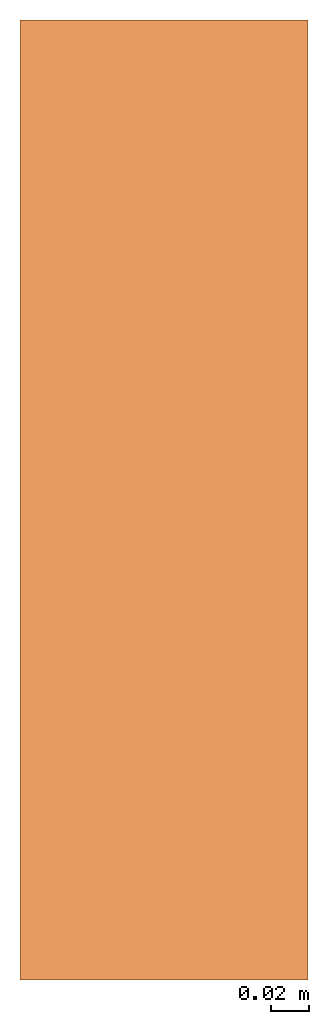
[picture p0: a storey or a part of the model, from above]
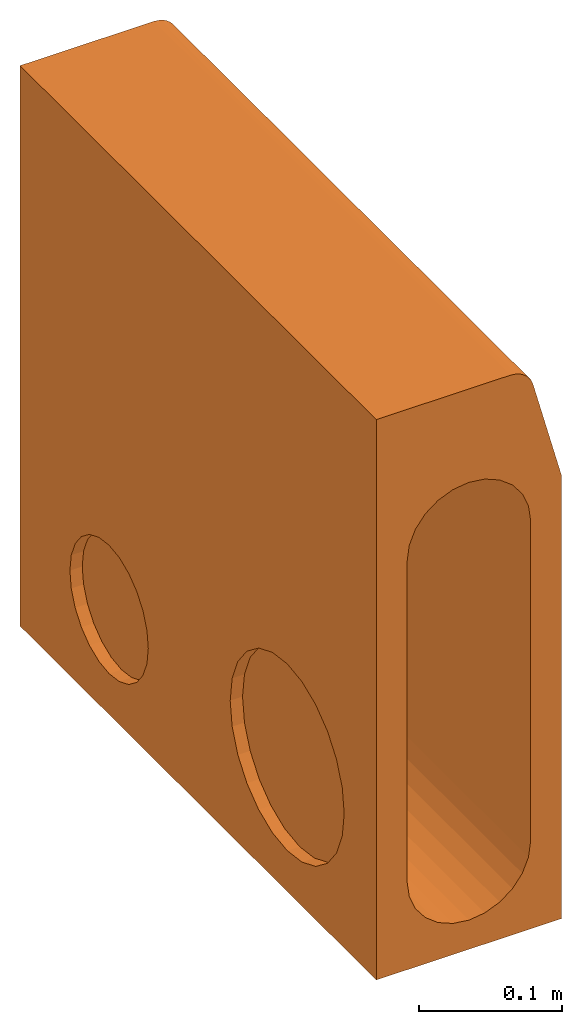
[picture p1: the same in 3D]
Properties of the parts of a building model (IFC2X3)

# File
Description: ViewDefinition [CoordinationView]
File name: 4923 - Blind Channel - 500mm LG.ifc
Time: 2013-09-18T17:36:49
Written by: Autodesk Revit 2013
Made in: 20120221_2030(x64)

# IfcProject, Project Number
LongName: Project Name; Phase: Project Status

# IfcSite, Default
RefLatitude: 42, 21, 30, 344238; RefLongitude: -71, -3, -35, -194702; RefElevation: 0 mm

# IfcBuilding
Pset_BuildingCommon - NumberOfStoreys: 2
Other - Project Issue Date: Issue Date; Project Address: Enter address here; Project Status: Project Status; Project Name: Project Name; Client Name: Owner; Project Number: Project Number

# IfcBuildingStorey (2)
Constraints - Elevation Base: 0
Graphics - Line Pattern: Center; Color: 0; Symbol: M_Level Head - Circle: M_Level Head - Circle; Symbol at End 1 Default: no; Line Weight: 1; Symbol at End 2 Default: yes
Identity Data - Structural: no; Building Story: yes
Dimensions - Computation Height: 0 mm
Name | LongName = Name | Elevation (mm) = Constraints, Elevation (mm)
T.O. Fnd. Wall | T.O. Fnd. Wall | -300
Level 1 | Level 1 | 0

# IfcBuildingElementProxy: 4923 - Blind Channel - 500mm LG, Civil-Drainage-Channel-ACO-KerbDrain-HB480(amar):4923 - Blind Channel - 500mm LG:4923 - Blind Channel - 500mm LG:481515
In: T.O. Fnd. Wall
Material: ACO Polymer Concrete.
Other - CreatedBy: www.aco.co.uk; Revision: 1
Materials and Finishes - Access Cover/Frame Colour: N/A; End Cap Colour: N/A; End Cap Material: N/A; Access Cover/Frame Finish: N/A; Channel Colour: Grey; Connection Pipe Material Colour: N/A; Access Cover/Frame Material: N/A; Connection Pipe Material: N/A; Channel Material: Vienite® Synthetic Resin Concrete
Dimensions - Mitre Void Start: 4355 mm; Mitre Void End: 4360 mm; Mitre Long end: 500 mm; Mitre Small End: 487 mm; Void Start I/O: 0 mm; Junction Start: 0 mm; Straight Void Start: 0 mm; junction void depth: 2000 mm; Void Depth: -355 mm; Void End I/O: 150 mm; I/O endcap void depth: 2000 mm; Void Width: 150 mm; Junction End: 150 mm; Void Length: 500 mm; Volume: 17011169 mm3
Constraints - Moves With Nearby Elements: no; Level: Level: Level 1
Phasing - Phase Created: Phase 1
Pset_BuildingElementProxyCommon - Reference: 4923 - Blind Channel - 500mm LG
General - SerialNumber: 0.000000; TagNumber: 0.000000
Construction - 25-11m external mitre: no; Access Unit: no; RH BS transition kerb: no; HB480-500: no; 7-6m external mitre: no; Centre Stone: no; Junction channel: no; RH inlet/outlet end cap: no; Closing end cap: no; Junction end cap: no; LH inlet/outlet end cap: no; Junction access unit: no; RH drop kerb: no; KDHB480 500_blindunit: yes; LH BS transition kerb: no; perforated centre stone: no; 10-8m external mitre: no; Bus stop kerb: no; cable loop: no; 25-11m internal mitre: no; LH drop kerb: no
Identity Data - Product Code: 4923; OmniClass Number: 23.70.50.24; Manufacturer: ACO Technologies plc - ACO Water Management Division; e-mail Sales: customersupport@aco.co.uk; URL: www.aco.co.uk; Fax: +44 (0)1462 815895; Installation guidelines: http://www.aco.co.uk/download.php?id=120; Type Comments: ACO KerbDrain HB480 half battered blind kerb unit 500mm long; Telephone: +44 (0)1462 816666; Product brochure: http://www.aco.co.uk/download.php?id=120; Address: ACO Business Park, Hitchin Road, Shefford, Bedfordshire, United Kingdom SG17 5TE; Product Page URL: http://www.aco.co.uk/product_detail.php?id=3; Maintenance guidelines: http://www.aco.co.uk/download.php?id=120 http://www.aco.co.uk/download.php?id=120; Model: ACO KerbDrain HB480; Price: POA - contact ACO; Assembly Code: D2040; OmniClass Title: Rainwater Removal; Model Description: Combined kerb and drainage system; Cost: 0; Assembly Description: Rain Water Drainage; e-mail Technical: technical@aco.co.uk
Data - Product Standard: BS EN 1433:2002, CE marked, Kitemarked; Connection Pipe O.D: N/A; Concrete Surround Volume - Load Class A 15 - D 400 - Grass or Asphalt Pavement: 0.18m³/m; Product Dimensions: 500mm x 150mm x 480mm (LxWxH); Invert Depth: 455mm; Hydraulic Performance: http://www.aco.co.uk/download.php?id=120; ACO Hydraulic Design Software: http://www.acodesign.co.uk; Concrete Surround Volume - Load Class A 15 - D 400 - Concrete Pavement: 0.19m³/m; Load Class: A 15 - D 400; Installation - Concrete Grade: Refer to brochure; Product Weight: 36.4 kg; Drainage Slot Width: N/A; Drainage Slot Intake area: N/A; Channel C.S.A: 0.04m²
Green Building Properties - Channel Recyclable: Fully recyclable; End Cap Recyclable: N/A; Access Cover/Frame Recycled Material Content: N/A; Channel Recycled Material Content: 20% minimum; Access Cover/Frame Recyclable: N/A; End Cap Recycled Material Content: N/A

# IfcOpeningElement: Opening (3)
In: Level 1
Dimensions - Volume: 2334075000 mm3; Thickness: 400 mm; Area: 5901750 mm2; Perimeter: 9790 mm
Constraints - Related to Mass: no; Room Bounding: yes; Height Offset From Level: 0 mm; Level: Level: Level 1
Structural - Structural: no; Enable Analytical Model: no
Phasing - Phase Created: Phase 1
Materials and Finishes - Structural Material: Earth
Analytical Properties - Roughness: 1; Absorptance: 0.1; Thermal mass: 543920; Thermal Resistance (R): 0.477897; Heat Transfer Coefficient (U): 2.0925
Construction - Function: 0; Default Thickness: 400 mm
Graphics - Coarse Scale Fill Color: 0

# IfcSlab: Floor:Generic Floor - 400mm, Floor:Generic Floor - 400mm:136426
In: Level 1
PredefinedType: FLOOR; Material: Earth 400 mm
Dimensions - Volume: 2334075000 mm3; Thickness: 400 mm; Area: 5901750 mm2; Perimeter: 9790 mm
Constraints - Related to Mass: no; Room Bounding: yes; Height Offset From Level: 0 mm; Level: Level: Level 1
Structural - Structural: no; Enable Analytical Model: no
Phasing - Phase Created: Phase 1
Pset_SlabCommon - Reference: Generic Floor - 400mm; IsExternal: no; LoadBearing: yes
Materials and Finishes - Structural Material: Earth
Analytical Properties - Roughness: 1; Absorptance: 0.1; Thermal mass: 543920; Thermal Resistance (R): 0.477897; Heat Transfer Coefficient (U): 2.0925
Construction - Function: 0; Default Thickness: 400 mm
Graphics - Coarse Scale Fill Color: 0
